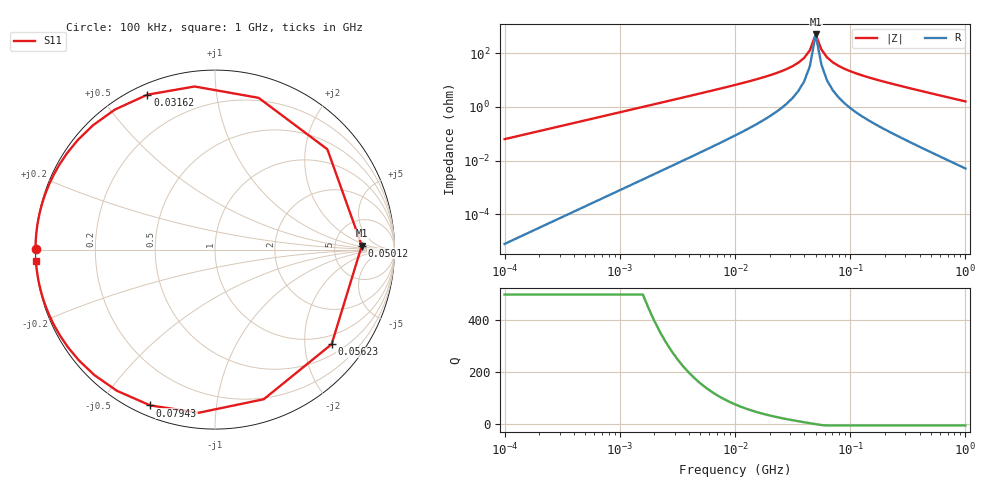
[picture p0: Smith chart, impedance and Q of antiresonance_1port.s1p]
# Hz S RI R 50
! golden: antiresonance_1port
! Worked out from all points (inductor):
!   81 points, 100 kHz to 1 GHz, reference 50 ohm
!   read as one part to ground: L = 100 nH near 100 kHz
!   highest |Z| = 496 ohm at 50.12 MHz (marker M1)
!   self-resonance near 52.14 MHz
!   S11 on the Smith chart (normalised r, x): 100 kHz: 0.00, +0.00; 31.62 MHz: 0.04, +0.65; 50.12 MHz: 9.83, +1.30; 56.23 MHz: 0.75, -2.63; 79.43 MHz: 0.04, -0.67; 1 GHz: 0.00, -0.03
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100000  -1 0.00251
354813.4  -1 0.00892
1000000  -0.9997 0.0251
3548134  -0.9956 0.0894
6309573  -0.9858 0.1599
1e7  -0.9631 0.2563
1.412538e7  -0.9218 0.3688
1.995262e7  -0.8241 0.5374
2.511886e7  -0.6797 0.6926
2.818383e7  -0.557 0.7805
3.162278e7  -0.3767 0.863
3.548134e7  -0.1139 0.9088
3.981072e7  0.2431 0.8455
4.466836e7  0.626 0.5591
5.011872e7  0.8179 0.0219
5.623413e7  0.6497 -0.5272
6.309573e7  0.2718 -0.8336
7.079458e7  -0.0909 -0.9091
7.943282e7  -0.3606 -0.8682
8.912509e7  -0.5461 -0.7869
1e8  -0.6723 -0.6989
1.122018e8  -0.7592 -0.6163
1.412538e8  -0.8644 -0.4777
1.778279e8  -0.9203 -0.3721
2.511886e8  -0.9624 -0.2586
3.548134e8  -0.9817 -0.1813
5.623413e8  -0.9929 -0.1137
1e9  -0.9978 -0.0637
